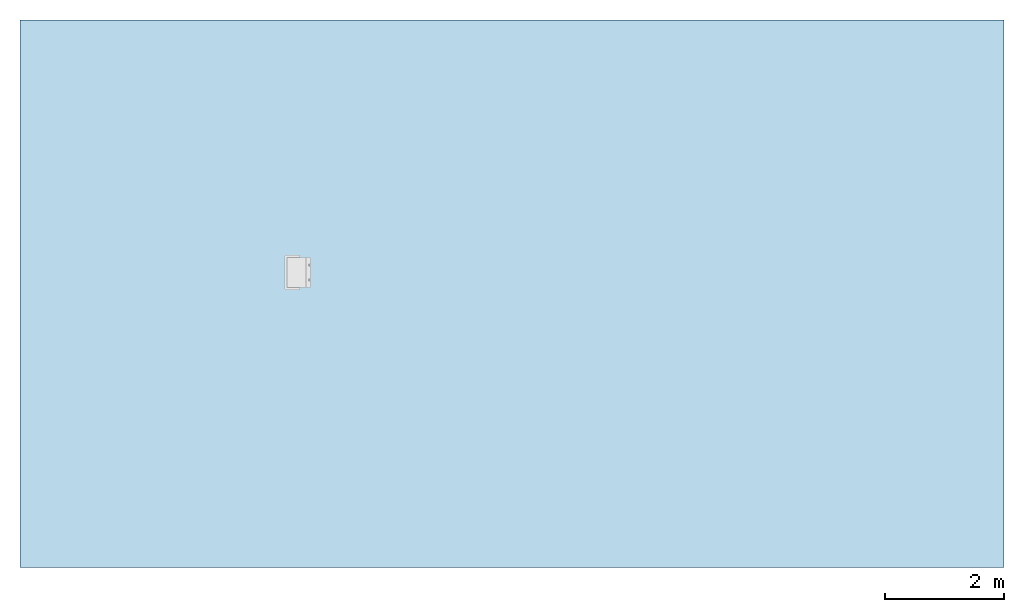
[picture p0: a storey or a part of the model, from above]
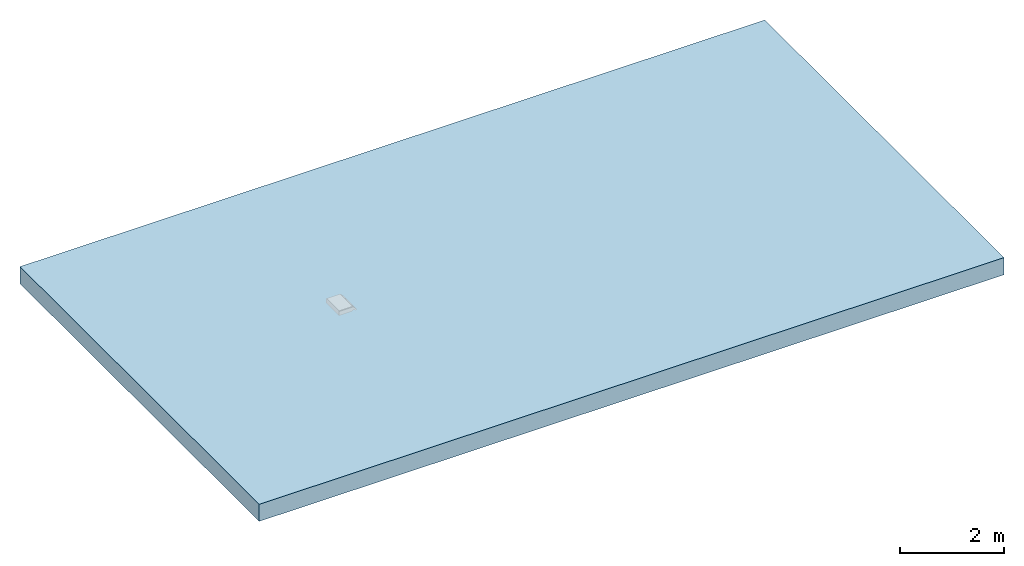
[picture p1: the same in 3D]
Properties of the parts of a building model (IFC2X3)

# File
Description: ViewDefinition [CoordinationView]
File name: 4977 - Top and shallow base assembly KDSP610.ifc
Time: 2013-09-04T10:21:12
Written by: Autodesk Revit 2013
Made in: 20120221_2030(x64)

# IfcProject, Project Number
LongName: Project Name; Phase: Project Status

# IfcSite, Default
RefLatitude: 42, 21, 30, 344238; RefLongitude: -71, -3, -35, -194702; RefElevation: 0 mm

# IfcBuilding
Pset_BuildingCommon - NumberOfStoreys: 1
Other - Client Name: Owner; Project Number: Project Number; Project Address: ## Street City, State Zip; Project Status: Project Status; Project Name: Project Name; Project Issue Date: Issue Date

# IfcBuildingStorey, Level 1
LongName: Level 1; Elevation: 0 mm
Constraints - Elevation Base: 0; Elevation: 0 mm
Graphics - Line Weight: 1; Symbol: M_Level Head - Circle: M_Level Head - Circle; Color: 0; Symbol at End 2 Default: yes; Line Pattern: Center; Symbol at End 1 Default: no
Dimensions - Computation Height: 0 mm
Identity Data - Name: Level 1; Structural: no; Building Story: yes

# IfcBuildingElementProxy: 4977 - Top and shallow base assembly KDSP610, Civil-Drainage-Channel-ACO-KerbDrain-SP Gully unit:4977 - Top and shallow base assembly KDSP610:4977 - Top and shallow base assembly KDSP610:312482
In: Level 1
Material: Ductile Iron, ACO Polmer Concrete., Gully
Phasing - Phase Created: New Construction
Constraints - Level: Level: Level 1; Moves With Nearby Elements: no
Dimensions - Volume: 33256128 mm3; Top and bottom 4979 void depth: 6000 mm; Gully Connector Void Start: 2000 mm; Gully Connector Void End: 2005 mm; Deep Base Void Depth: 6000 mm; Shallow Base Depth: 770 mm
Pset_BuildingElementProxyCommon - Reference: 4977 - Top and shallow base assembly KDSP610
Identity Data - Telephone: +44 (0)1462 816666; Fax: +44 (0)1462 815895; URL: www.aco.co.uk; Address: ACO Business Park, Hitchin Road, Shefford, Bedfordshire, United Kingdom SG17 5TE; Assembly Description: Rain Water Drainage; Price: POA - contact ACO; Product Page URL: http://www.aco.co.uk/product_detail.php?id=3; Maintenance guidelines: http://www.aco.co.uk/download.php?id=120; Product Code: 4977; OmniClass Number: 23.70.50.24; OmniClass Title: Rainwater Removal; Assembly Code: D2040; Model: ACO KerbDrain Splayed Gully Units; Product brochure: http://www.aco.co.uk/download.php?id=120; e-mail Sales: customersupport@aco.co.uk; Installation guidelines: http://www.aco.co.uk/download.php?id=120; Cost: 0; e-mail Technical: technical@aco.co.uk; Model Description: Combined kerb and drainage system; Type Comments: ACO KerbDrain Splayed Gully Units - Top & Shallow Base Assembly KDSP610; Manufacturer: ACO Technologies plc - ACO Water Management Division
General - TagNumber: 0.000000; SerialNumber: 0.000000
Green Building Properties - Gully Cover/Frame Recycled Material Content: Between 40% - 90%; Gully Cover/Frame Recyclable: Fully recyclable; Gully Base Recycled Material Content: 20% minimum; Gully Base Recyclable: Fully recyclable
Construction - Top assembly: yes; Top and road gully connector: no; Shallow base: yes; Deep Base: no; Top and roddable deep base assembly KDSP612RE: no
Data - Product Dimensions: 500mm x 390mm x 870mm (LxWxH); Load Class: A 15 - D 400; ACO Hydraulic Design Software: http://www.acodesign.co.uk; Invert Depth: 845mm; Hydraulic Performance: http://www.aco.co.uk/download.php?id=120; Product Standard: BS EN 1433:2002, CE marked, Kitemarked; Drainage Slot Intake area: 14592mm²/m; Installation - Concrete Grade: Refer to brochure; Product Weight: 100.9 Kg; Drainage Slot Width: 50mm
Materials and Finishes - Gully Cover/Frame Material: Ductile Iron; Gully Base Colour: Brown; Gully Base Material: Vienite® Synthetic Resin Concrete; Gully Cover/Frame Colour: Black; Gully Cover/Frame Finish: Water Based Paint Coating
Other - Revision: 1; CreatedBy: www.aco.co.uk

# IfcOpeningElement: Opening (3)
In: Level 1
Dimensions - Thickness: 400 mm; Area: 151275000 mm2; Volume: 60509762589 mm3; Perimeter: 51360 mm
Constraints - Height Offset From Level: 0 mm; Related to Mass: no; Room Bounding: yes; Level: Level: Level 1
Phasing - Phase Created: New Construction
Structural - Enable Analytical Model: no; Structural: no
Construction - Function: 0; Default Thickness: 400 mm
Graphics - Coarse Scale Fill Color: 0
Analytical Properties - Absorptance: 0.1; Roughness: 1
Materials and Finishes - Structural Material: Plant

# IfcSlab: Floor:Generic Floor - 400mm, Floor:Generic Floor - 400mm:193825
In: Level 1
PredefinedType: FLOOR; Material: Plant 400 mm
Dimensions - Thickness: 400 mm; Area: 151275000 mm2; Volume: 60509762589 mm3; Perimeter: 51360 mm
Constraints - Height Offset From Level: 0 mm; Related to Mass: no; Room Bounding: yes; Level: Level: Level 1
Phasing - Phase Created: New Construction
Structural - Enable Analytical Model: no; Structural: no
Pset_SlabCommon - Reference: Generic Floor - 400mm; IsExternal: no; LoadBearing: yes
Construction - Function: 0; Default Thickness: 400 mm
Graphics - Coarse Scale Fill Color: 0
Analytical Properties - Absorptance: 0.1; Roughness: 1
Materials and Finishes - Structural Material: Plant
